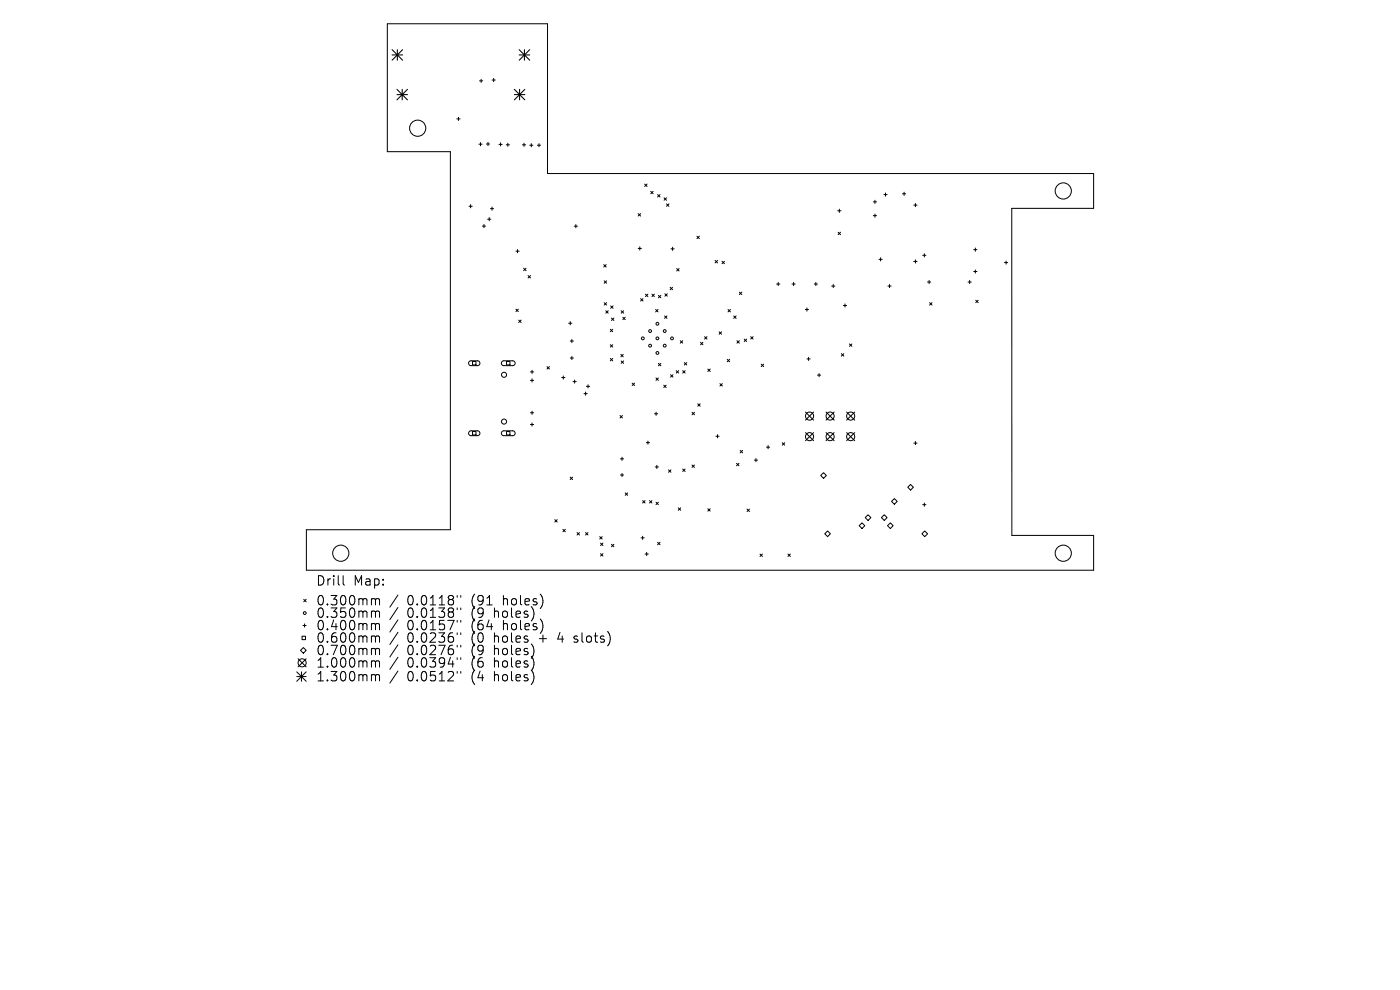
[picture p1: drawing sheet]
<svg xmlns="http://www.w3.org/2000/svg" width="297mm" height="210mm" viewBox="0 0 297 210" stroke-linecap="round" stroke-linejoin="round" font-family="sans-serif">
<defs><g id="words">
<g font-size="2.8">
<text x="67" y="124.5">Drill</text>
<text x="75" y="124.5">Map:</text>
<text x="67" y="128.7">0.300mm</text>
<text x="67" y="131.3">0.350mm</text>
<text x="86.4" y="128.7">0.0118&quot;</text>
<text x="86.4" y="131.3">0.0138&quot;</text>
<text x="100.1" y="128.7">(91</text>
<text x="100.1" y="131.3">(9</text>
<text x="105.1" y="131.3">holes)</text>
<text x="107" y="128.7">holes)</text>
<text x="67" y="134">0.400mm</text>
<text x="67" y="136.6">0.600mm</text>
<text x="86.4" y="134">0.0157&quot;</text>
<text x="86.4" y="136.6">0.0236&quot;</text>
<text x="100.1" y="134">(64</text>
<text x="100.1" y="136.6">(0</text>
<text x="105.1" y="136.6">holes</text>
<text x="107" y="134">holes)</text>
<text x="114.8" y="136.6">+</text>
<text x="119" y="136.6">4</text>
<text x="122.6" y="136.6">slots)</text>
<text x="67" y="139.3">0.700mm</text>
<text x="67" y="141.9">1.000mm</text>
<text x="86.4" y="139.3">0.0276&quot;</text>
<text x="86.4" y="141.9">0.0394&quot;</text>
<text x="100.1" y="139.3">(9</text>
<text x="100.1" y="141.9">(6</text>
<text x="105.1" y="139.3">holes)</text>
<text x="105.1" y="141.9">holes)</text>
<text x="67" y="144.8">1.300mm</text>
<text x="86.4" y="144.8">0.0512&quot;</text>
<text x="100.1" y="144.8">(4</text>
<text x="105.1" y="144.8">holes)</text>
</g>
</g></defs>
<g fill="none" stroke="#000" stroke-width=".21">
<path d="M82.2 5h34v31.8h115.8v7.4h-17.4l.1 69.4h17.3v7.4h-167v-8.6h30.5v-80.2h-13.3zM101.7 17.2h.7M102.1 16.8v.7M104.4 17h.7M104.7 16.6v.7M96.9 25.2h.7M97.3 24.9v.7M101.6 30.6h.7M101.9 30.2v.7M103.2 30.5h.7M103.5 30.2v.7M105.8 30.6h.7"/>
<path d="M106.2 30.3v.7M107.4 30.7h.7M107.7 30.4v.7M110.8 30.7h.7M111.2 30.4v.7M112.4 30.8h.7M112.7 30.5v.6M114 30.8h.7M114.3 30.5v.6M136.8 39l.5 .6M137.3 39l-.5 .6M99.5 43.8h.7"/>
<path d="M99.8 43.4v.7M102.3 48h.7M102.7 47.6v.7M103.4 46.5h.7M103.8 46.2v.6M104 44.3h.7M104.4 43.9v.7M109.5 53.3h.6M109.8 52.9v.7M111.1 56.9l.5 .5M111.6 56.9l-.5 .5M112 58.5l.5 .5"/>
<path d="M112.5 58.5l-.5 .5M121.8 48h.7M122.2 47.6v.7M128.1 56.1l.5 .5M128.2 59.6l.5 .5M128.6 56.1l-.5 .5M128.7 59.6l-.5 .5M135.4 45.3l.5 .5M135.4 52.7h.7M135.7 52.4v.6M135.9 45.3l-.5 .5M138 40.6l.6 .5"/>
<path d="M138.6 40.6l-.6 .5M139.5 41.3l.5 .5M140 41.3l-.5 .5M140.9 42l.5 .5M141.4 42l-.5 .5M141.4 43.3l.5 .5M141.9 43.3l-.5 .5M142.3 52.8h.7M142.7 52.4v.7M143.6 57l.5 .5M144.1 57l-.5 .5M147.8 50.1l.6 .5"/>
<path d="M148.4 50.1l-.6 .5M151.7 55.3l.5 .5M152.2 55.3l-.5 .5M153.2 55.4l.5 .5M153.7 55.4l-.5 .5M165.1 59.9v.7M168.4 59.9v.7M173.1 59.9v.7M177.7 44.7h.7M177.8 49.3l.5 .5M178.1 44.4v.7M178.3 49.3l-.5 .5"/>
<path d="M185.3 42.8h.7M185.3 45.7h.7M185.6 42.5v.7M185.6 45.4v.7M186.5 55h.7M186.8 54.7v.7M187.5 41.3h.7M187.8 40.9v.7M191.5 41.1h.6M191.8 40.8v.7M193.9 43.5h.6M193.9 55.5h.6"/>
<path d="M194.2 43.2v.7M194.2 55.1v.7M195.7 54.2h.7M196.1 53.8v.7M196.8 59.8h.6M197.1 59.5v.7M205.4 59.8h.7M205.7 59.5v.7M206.6 53h.7M206.6 57.6h.7M206.9 52.6v.7M206.9 57.2v.7"/>
<path d="M213.1 55.7h.7M213.4 55.4v.6M99.6 76.7l.3-.2h1.5l.3 .3 .1 .3-.4 .5h-1.6l-.4-.4zM100.2 76.7h.8v.7h-.8zM106.5 76.7l.3-.2h2.1l.3 .3 .1 .3-.4 .5h-2.1l-.4-.4zM107.5 76.7h.7v.7h-.7zM109.5 65.6l.5 .5M110 65.6l-.5 .5M110 67.9l.6 .5M110.6 67.9l-.6 .5M112.5 78.9h.7M112.9 78.5v.7"/>
<path d="M116 77.8l.6 .5M116.6 77.8l-.6 .5M119.5 79.7v.7M120.6 68.6h.7M121 68.2v.7M121 72.3h.7M121 75.9h.7M121.3 72v.7M121.3 75.6v.7M128.2 64.2l.5 .5M128.5 65.9l.5 .5M128.7 64.2l-.5 .5"/>
<path d="M129 65.9l-.5 .5M129.5 69.9l.5 .5M129.5 73.1l.5 .5M129.5 76l.5 .5M129.5 64.9l.6 .5M129.7 67.5l.5 .5M130 69.9l-.5 .5M130 73.1l-.5 .5M130 76l-.5 .5M130.1 64.9l-.6 .5M130.2 67.5l-.5 .5M131.7 75.2l.5 .5"/>
<path d="M131.8 65.9l.5 .5M131.8 76.6l.5 .5M132.1 67.3l.5 .5M132.2 75.2l-.5 .5M132.3 65.9l-.5 .5M132.3 76.6l-.5 .5M132.6 67.3l-.5 .5M135.9 63.3l.5 .6M136.4 63.3l-.5 .6M136.9 62.4l.5 .5M137.4 62.4l-.5 .5M138.3 62.4l.5 .5"/>
<path d="M138.8 62.4l-.5 .5M139.1 65.6l.5 .6M139.6 65.6l-.5 .6M139.7 62.7l.5 .5M139.7 77.1l.5 .5M140.2 62.7l-.5 .5M140.2 77.1l-.5 .5M141 67l.5 .5M141.1 62.3l.5 .5M141.5 67l-.5 .5M141.6 62.3l-.5 .5M142.2 60.9l.5 .6"/>
<path d="M142.3 79.5l.5 .5M142.7 60.9l-.5 .6M142.8 79.5l-.5 .5M143.5 78.6l.5 .5M144 78.6l-.5 .5M144.3 72.3l.5 .5M144.8 72.3l-.5 .5M144.8 78.6l.5 .5M145.2 76.9l.5 .5M145.3 78.6l-.5 .5M145.7 76.9l-.5 .5M148.6 72.6l.5 .5"/>
<path d="M149.1 72.6l-.5 .5M149.5 71.4l.5 .5M150 71.4l-.5 .5M150.2 78.3l.5 .5M150.7 78.3l-.5 .5M152.6 70.4l.5 .5M153.1 70.4l-.5 .5M154.3 76.2l.5 .5M154.4 65.6l.6 .6M154.8 76.2l-.5 .5M155 65.6l-.6 .6M155.6 67l.6 .5"/>
<path d="M156.2 67l-.6 .5M156.3 72.3l.6 .5M156.9 72.3l-.6 .5M156.9 62l.5 .5M157.4 62l-.5 .5M157.9 71.9l.5 .5M158.4 71.9l-.5 .5M159.3 71.4l.5 .5M159.8 71.4l-.5 .5M161.5 77.3l.5 .5M162 77.3l-.5 .5M164.8 60.3h.6"/>
<path d="M168 60.3h.7M170.8 65.7h.7M171.2 65.3v.7M171.2 76.1h.7M171.5 75.8v.7M172.7 60.3h.7M173.4 79.6h.7M173.8 79.2v.7M176.4 60.7h.7M176.8 60.3v.7M178.5 75l.5 .5M178.9 64.8h.7"/>
<path d="M179 75l-.5 .5M179.3 64.5v.6M180.2 73l.5 .5M180.7 73l-.5 .5M188.4 60.7h.7M188.7 60.3v.7M197.2 64.2l.5 .5M197.7 64.2l-.5 .5M207 63.7l.5 .5M207.5 63.7l-.5 .5M99.6 91.5l.3-.1h1.5l.3 .2 .1 .4-.4 .4h-1.6l-.4-.4zM100.2 91.5h.8v.8h-.8z"/>
<path d="M106.5 91.5l.3-.1h2.1l.3 .2 .1 .4-.4 .4h-2.1l-.4-.4zM107.5 91.5h.7v.8h-.7zM112.5 80.7h.7M112.5 87.6h.7M112.5 90h.7M112.9 80.3v.7M112.9 87.2v.7M112.9 89.7v.7M119.2 80.1h.6M121.6 80.9h.6M121.9 80.6v.7M123.9 83.5h.7"/>
<path d="M124.2 83.2v.6M124.4 82h.7M124.7 81.6v.7M131.5 88.1l.5 .6M131.6 97.3h.7M132 97v.7M132 88.1l-.5 .6M134.1 81.3l.5 .5M134.6 81.3l-.5 .5M137.1 93.9h.7M137.5 93.6v.6M138.8 87.8h.7"/>
<path d="M139 99.1h.7M139.2 80.2l.5 .5M139.2 87.4v.7M139.3 98.7v.7M139.7 80.2l-.5 .5M140.8 81.7l.5 .5M141.3 81.7l-.5 .5M141.8 99.7l.5 .5M142.3 99.7l-.5 .5M144.8 99.5l.5 .5M145.3 99.5l-.5 .5M146.8 98.6l.5 .6"/>
<path d="M146.8 87.5l.5 .5M147.3 98.6l-.5 .6M147.3 87.5l-.5 .5M148 85.7l.5 .5M148.5 85.7l-.5 .5M151.9 92.5h.7M152.2 92.2v.7M152.7 81.4l.5 .5M153.2 81.4l-.5 .5M156.3 98.3l.5 .5M156.8 98.3l-.5 .5M157 95.5l.5 .6"/>
<path d="M157.5 95.5l-.5 .6M160 97.6h.7M160.4 97.3v.6M162.6 94.9h.7M162.9 94.5v.7M166 93.9l.5 .5M166.5 93.9l-.5 .5M170.9 87.4l1.7 1.7M170.9 91.8l1.7 1.7M172.6 87.4l-1.7 1.7M172.6 91.8l-1.7 1.7M175.2 91.8l1.8 1.7"/>
<path d="M175.2 87.4l1.8 1.7M177 87.4l-1.8 1.7M177 91.8l-1.8 1.7M179.6 91.8l1.7 1.7M179.6 87.4l1.7 1.7M181.3 87.4l-1.7 1.7M181.3 91.8l-1.7 1.7M193.9 94h.6M194.2 93.7v.6M117.7 110.2l.5 .5M118.2 110.2l-.5 .5M119.4 112.3l.5 .5"/>
<path d="M119.9 112.3l-.5 .5M121 101.2l.5 .5M121.5 101.2l-.5 .5M122.4 113l.5 .5M122.9 113l-.5 .5M124.2 113l.5 .5M124.7 113l-.5 .5M127.2 113.8l.5 .5M127.4 115.2l.5 .5M127.4 117.4l.5 .6M127.7 113.8l-.5 .5M127.9 115.2l-.5 .5"/>
<path d="M127.9 117.4l-.5 .6M129.7 115.5l.5 .5M130.2 115.5l-.5 .5M131.6 100.8h.7M132 100.4v.7M132.6 104.6l.6 .5M133.2 104.6l-.6 .5M136 114.1h.7M136.3 106.2l.5 .5M136.3 113.7v.7M136.8 106.2l-.5 .5M136.8 117.5h.7"/>
<path d="M137.2 117.2v.7M137.8 106.2l.5 .5M138.3 106.2l-.5 .5M139.2 106.5l.5 .6M139.5 115l.5 .6M139.7 106.5l-.5 .6M140 115l-.5 .6M143.9 107.7l.5 .6M144.4 107.7l-.5 .6M150.2 107.9l.5 .5M150.7 107.9l-.5 .5M158.5 108l.5 .5"/>
<path d="M159 108l-.5 .5M161.2 117.5l.5 .5M161.7 117.5l-.5 .5M167.2 117.5l.5 .5M167.7 117.5l-.5 .5M174.1 100.9l.6-.6 .6 .6-.6 .6zM175 113.2l.6-.6 .6 .6-.6 .6zM182.3 111.5l.6-.6 .6 .6-.6 .6zM183.6 109.8l.6-.6 .6 .6-.6 .6zM187 109.8l.6-.6 .6 .6-.6 .6zM188.3 111.5l.6-.6 .6 .6-.6 .6zM189.1 106.4l.6-.6 .6 .6-.6 .6z"/>
<path d="M192.6 103.4l.6-.6 .6 .6-.6 .6zM195.6 113.2l.6-.6 .6 .6-.6 .6zM195.7 107.1h.7M196.1 106.7v.7M63.2 139.7l1.8 1.8M63.8 138l.6-.6 .6 .6-.6 .6zM64.1 135h.7v.7h-.7zM64.3 132.7h.7M64.4 127.1l.6 .6M64.6 132.3v.7M65 127.1l-.6 .6M65 139.7l-1.8 1.8"/>
<path d="M72.8 122.1v1.7l.3 .3M79.1 127l.5 .1 .1 .2M79.1 129.6h.3l.3 .3M79.1 132.3h.3l.3 .3M79.1 134.9h.3l.3 .3M79.1 137.5l.5 .1 .1 .2M79.7 127.3l.2-.3 .5 .1 .1 1.2M79.7 127.3v1M79.7 129.9v1.1M79.7 132.6v1M79.7 135.2v1M79.7 137.8v1.1"/>
<path d="M79.7 129.9l.2-.3 .5 .1 .1 1.3M79.7 132.6l.2-.3 .5 .1 .1 1.2M79.7 135.2l.2-.3 .5 .1 .1 1.2M79.7 137.8l.2-.3 .5 .1 .1 1.3M84.4 126.2l-1.7 2.6M84.4 128.9l-1.7 2.5M84.4 131.5l-1.7 2.6M84.4 134.1l-1.7 2.6M84.4 136.8l-1.7 2.6M84.4 139.4l-1.7 2.6M97 126.3v.4M97 129v.3"/>
<path d="M97 131.6v.4M97 134.2v.4M97 136.9v.4M97 139.5v.4M97.8 126.3v.4M97.8 129v.3M97.8 131.6v.4M97.8 134.2v.4M97.8 136.9v.4M97.8 139.5v.4M121.8 136.1l.1 .1M121.8 135v.5"/>
<path d="M63 142.5l2 2M63 143.5h2M64 142.5v2M65 142.5l-2 2M79.1 140.2l.5 .1 .1 .2M79.1 143.1h.3l.3 .3M79.7 140.5v1M79.7 143.4v1M79.7 140.5l.2-.3 .5 .1 .1 1.2M79.7 143.4l.2-.3 .5 .1 .1 1.2M84.4 142.3l-1.7 2.6M97 142.4v.4"/>
<path d="M97.8 142.4v.4"/>
<circle cx="88.6" cy="27.2" r="1.72"/>
<circle cx="225.6" cy="40.5" r="1.72"/>
<circle cx="106.9" cy="79.5" r=".54"/>
<circle cx="136.4" cy="71.8" r=".3"/>
<circle cx="137.9" cy="70.2" r=".3"/>
<circle cx="137.9" cy="73.3" r=".3"/>
<circle cx="139.5" cy="68.7" r=".3"/>
<circle cx="139.5" cy="74.9" r=".3"/>
<circle cx="139.5" cy="71.8" r=".3"/>
<circle cx="141" cy="70.2" r=".3"/>
<circle cx="141" cy="73.3" r=".3"/>
<circle cx="142.6" cy="71.8" r=".3"/>
<circle cx="106.9" cy="89.4" r=".54"/>
<circle cx="171.7" cy="92.6" r=".86"/>
<circle cx="171.7" cy="88.3" r=".86"/>
<circle cx="176.1" cy="92.6" r=".86"/>
<circle cx="176.1" cy="88.3" r=".86"/>
<circle cx="180.5" cy="92.6" r=".86"/>
<circle cx="180.5" cy="88.3" r=".86"/>
<circle cx="72.3" cy="117.4" r="1.72"/>
<circle cx="225.6" cy="117.4" r="1.72"/>
<circle cx="64.7" cy="130" r=".3"/>
<circle cx="64.1" cy="140.6" r=".86"/>
</g>
<g fill="none" stroke="#000" stroke-width=".22">
<path d="M83.2 10.5l2.2 2.3M83.2 11.7h2.2M84.2 19l2.2 2.2M84.3 10.5v2.3M85.3 19v2.2M85.4 10.5l-2.2 2.3M86.4 19l-2.2 2.2M109.1 19l2.2 2.2M110.1 11.7h2.3M110.1 10.5l2.3 2.3M110.2 19v2.2M111.3 10.5v2.3"/>
<path d="M111.3 19l-2.2 2.2M112.4 10.5l-2.3 2.3M84.2 20.1h2.2M109.1 20.1h2.2"/>
</g>
<use href="#words"/>
</svg>
